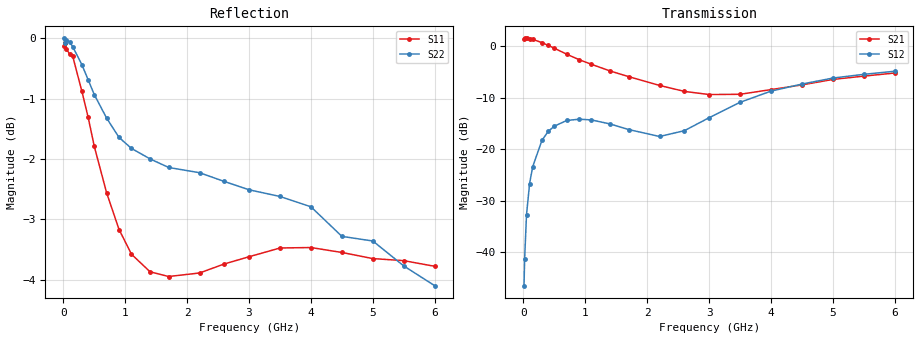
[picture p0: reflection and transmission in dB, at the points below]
! Infineon Technologies  Discrete & RF Semiconductors
! BFS17W
! Si NPN RF Bipolar Junction Transistor in SOT323
! VCE = 2.5 V  IC = 0.3 mA
! Common Emitter S-Parameters:  August  1999
# GHz  S  MA  R  50
!  f  S11  S21  S12  S22
! GHz  MAG  ANG  MAG  ANG  MAG  ANG  MAG  ANG
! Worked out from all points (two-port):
!   36 points, 10 MHz to 6 GHz, reference 50 ohm
!   highest |S21| = 1.56 dB at 50 MHz (marker M1); lowest = -9.4 dB at 3 GHz (marker M2)
!   |S21| within 3 dB of the highest: start of sweep to 684 MHz
!   lowest |S11| = -3.9 dB at 1.7 GHz (marker M3), VSWR 4.48, Z = 11.2 - j2.78 ohm
!   |S11| at or under -10 dB: nowhere
!   |S22| runs from -4.1 to 0.0 dB; largest |S21 - S12| = 1.2
!   S11 on the Smith chart (normalised r, x): 10 MHz: 30, -55; 300 MHz: 0.27, -2.08; 700 MHz: 0.24, -0.78; 1.4 GHz: 0.23, -0.19; 3 GHz: 0.24, +0.39; 6 GHz: 0.50, +1.09
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0.01  0.9848 -1.6  1.192 179.4  0.0047 87.7  0.9999 0.0
0.02  0.9912 -3.8  1.194 177.1  0.0086 89.4  0.992 -1.0
0.05  0.9795 -8.8  1.197 172.3  0.023 86.1  0.9975 -2.7
0.1  0.9707 -17.3  1.179 165.1  0.0463 79.3  0.9932 -5.3
0.15  0.9668 -26.8  1.169 157.3  0.0675 73.2  0.9843 -7.9
0.3  0.9036 -50.8  1.089 136.2  0.1221 58.8  0.9508 -14.8
0.4  0.8604 -65.5  1.022 123.3  0.1488 50.2  0.924 -18.8
0.5  0.8136 -79.0  0.96 112.3  0.1676 43.1  0.8981 -22.3
0.7  0.7444 -102.3  0.839 93.2  0.1902 31.8  0.8586 -28.4
0.9  0.6944 -121.3  0.743 78.2  0.1957 23.5  0.8277 -34.1
1.1  0.6625 -137.6  0.669 65.7  0.1926 17.9  0.8106 -39.7
1.4  0.6407 -157.1  0.577 51.4  0.176 13.5  0.7946 -48.3
1.7  0.6349 -173.3  0.508 41.0  0.1553 14.7  0.7817 -57.6
2.2  0.6392 164.4  0.417 30.5  0.1329 31.8  0.7739 -73.4
2.6  0.6503 149.3  0.365 28.0  0.1513 50.6  0.7611 -86.7
3  0.6593 135.8  0.34 30.4  0.2023 60.2  0.7491 -99.4
3.5  0.6704 121.1  0.342 35.4  0.2858 60.7  0.7396 -115.9
4  0.671 108.9  0.38 37.6  0.3672 55.2  0.7252 -133.1
4.5  0.6647 98.4  0.422 36.5  0.4301 48.1  0.6854 -148.8
5  0.657 90.3  0.477 33.2  0.492 41.2  0.6794 -162.1
5.5  0.6544 83.7  0.514 29.0  0.5348 34.5  0.6478 -175.8
6  0.6474 78.4  0.551 24.5  0.5732 28.3  0.6239 172.3
